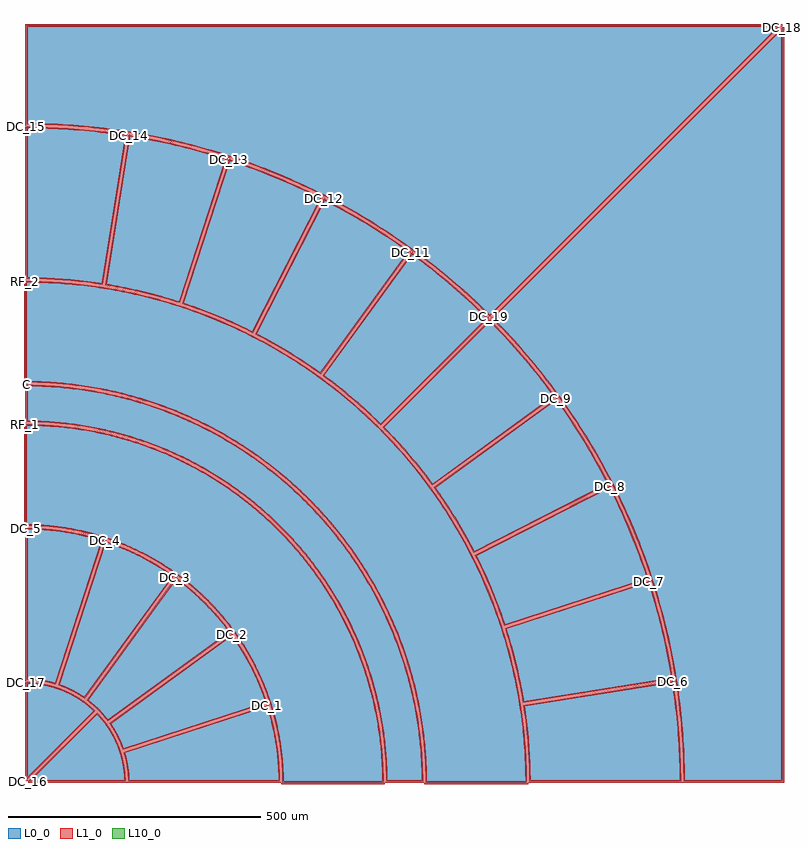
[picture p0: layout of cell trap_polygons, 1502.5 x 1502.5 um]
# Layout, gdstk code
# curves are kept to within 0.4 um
import gdstk
lib = gdstk.Library(unit=1e-6, precision=1e-09)
def P(c, l, *ps):  # polygons
    for p in ps: c.add(gdstk.Polygon(p, *l))
L0_0 = (0, 0)
L1_0 = (1, 0)
L10_0 = (10, 0)

trap_polygons = lib.new_cell('trap_polygons')
P(trap_polygons, L0_0, [(168.53,172.066),(123.841,214.523),(77.191,254.817),(28.686,292.857),(-21.566,328.558),(-73.452,361.839),(-108.893,382.645),(-135.896,397.51),(-190.918,425.3),(-247.195,450.454),(-304.6,472.915),(-363.004,492.633),(-422.275,509.563),(-452.195,516.971),(-492.346,525.742),(-532.753,533.24),(-563.203,538.025),(-624.399,545.425),(-685.878,549.919),(-747.5,551.498),(-747.5,747.5),(743.964,747.5)],
  [(747.5,743.964),(747.5,-747.5),(551.498,-747.5),(549.919,-685.878),(545.425,-624.399),(538.025,-563.203),(533.24,-532.753),(525.742,-492.346),(516.971,-452.195),(509.563,-422.275),(492.633,-363.004),(472.915,-304.6),(450.454,-247.195),(425.3,-190.918),(397.51,-135.896),(382.645,-108.893),(361.839,-73.452),(328.558,-21.566),(292.857,28.686),(254.817,77.191),(214.523,123.841),(172.066,168.53)],
  [(-747.5,-551.516),(-727.732,-552.753),(-709.676,-555.639),(-690.507,-560.625),(-673.334,-566.903),(-656.811,-574.734),(-639.808,-584.894),(-625.083,-595.734),(-611.418,-607.883),(-747.5,-743.964)],
  [(-743.964,-747.5),(-607.883,-611.418),(-595.734,-625.083),(-584.894,-639.808),(-574.734,-656.811),(-566.903,-673.334),(-560.625,-690.507),(-555.639,-709.676),(-552.753,-727.732),(-551.516,-747.5)],
  [(-747.5,546.498),(-695.239,545.343),(-643.067,542.083),(-601.451,537.962),(-549.652,530.927),(-596.583,234.619),(-636.096,239.969),(-675.791,243.733),(-707.636,245.599),(-747.5,246.497)],
  [(-544.714,530.144),(-503.534,522.858),(-452.424,511.888),(-401.798,498.866),(-351.738,483.815),(-444.443,198.497),(-482.633,209.962),(-521.251,219.89),(-560.235,228.265),(-591.644,233.837)],
  [(-346.983,482.27),(-297.636,465.022),(-249.025,445.8),(-201.229,424.633),(-163.63,406.323),(-299.827,139.02),(-335.754,156.318),(-372.343,172.165),(-409.537,186.535),(-439.688,196.952)],
  [(-159.175,404.053),(-113.134,379.298),(-68.129,352.708),(-32.919,330.142),(10.04,300.358),(-166.296,57.652),(-199.074,80.357),(-225.934,97.566),(-260.261,117.853),(-295.372,136.75)],
  [(14.085,297.419),(55.686,265.767),(95.978,232.463),(127.224,204.668),(164.994,168.53),(-47.138,-43.603),(-70.108,-21.468),(-99.798,5.149),(-130.529,30.556),(-162.251,54.713)],
  [(168.53,164.994),(204.668,127.224),(232.463,95.978),(265.767,55.686),(297.419,14.085),(54.713,-162.251),(30.556,-130.529),(5.149,-99.798),(-21.468,-70.108),(-43.603,-47.138)],
  [(300.358,10.04),(330.142,-32.919),(352.708,-68.129),(379.298,-113.134),(404.053,-159.175),(136.75,-295.372),(117.853,-260.261),(97.566,-225.934),(80.357,-199.074),(57.652,-166.296)],
  [(406.323,-163.63),(424.633,-201.229),(445.8,-249.025),(465.022,-297.636),(482.27,-346.983),(196.952,-439.688),(186.535,-409.537),(172.165,-372.343),(156.318,-335.754),(139.02,-299.827)],
  [(483.815,-351.738),(498.866,-401.798),(511.888,-452.424),(522.858,-503.534),(530.144,-544.714),(233.837,-591.644),(228.265,-560.235),(219.89,-521.251),(209.962,-482.633),(198.497,-444.443)],
  [(530.927,-549.652),(537.962,-601.451),(542.083,-643.067),(545.343,-695.239),(546.498,-747.5),(246.497,-747.5),(245.599,-707.636),(243.733,-675.791),(239.969,-636.096),(234.619,-596.583)],
  [(-747.5,-246.506),(-708.271,-248.232),(-673.175,-252.395),(-634.632,-259.896),(-596.789,-270.376),(-689.497,-555.702),(-704.078,-551.749),(-717.42,-549.125),(-732.411,-547.262),(-747.5,-546.515)],
  [(-592.034,-271.921),(-555.259,-285.685),(-523.167,-300.49),(-488.828,-319.534),(-456.076,-341.196),(-632.417,-583.908),(-643.771,-576.427),(-656.94,-569.024),(-670.623,-562.619),(-684.742,-557.247)],
  [(-452.031,-344.134),(-424.294,-366.036),(-395.363,-392.586),(-368.589,-421.309),(-344.134,-452.031),(-586.847,-628.372),(-596.319,-616.604),(-605.571,-606.639),(-616.604,-596.319),(-628.372,-586.847)],
  [(-341.196,-456.076),(-319.534,-488.828),(-300.49,-523.167),(-285.685,-555.259),(-271.921,-592.034),(-557.247,-684.742),(-562.619,-670.623),(-569.024,-656.94),(-576.427,-643.771),(-583.908,-632.417)],
  [(-270.376,-596.789),(-259.896,-634.632),(-252.395,-673.175),(-248.232,-708.271),(-246.506,-747.5),(-546.515,-747.5),(-547.262,-732.411),(-549.125,-717.42),(-551.749,-704.078),(-555.702,-689.497)],
  [(-747.5,36.496),(-710.604,35.513),(-667.673,32.179),(-631.067,27.456),(-594.723,21.02),(-558.721,12.886),(-523.14,3.072),(-488.059,-8.401),(-447.865,-23.848),(-414.13,-38.823),(-381.134,-55.363),(-348.951,-73.434),(-312.524,-96.397),(-282.342,-117.641),(-253.189,-140.278),(-225.13,-164.258),(-193.861,-193.861),(-164.258,-225.13),(-140.278,-253.189),(-117.641,-282.342),(-96.397,-312.524),(-73.434,-348.951),(-55.363,-381.134),(-38.823,-414.13),(-23.848,-447.865),(-8.401,-488.059),(3.072,-523.14),(12.886,-558.721),(21.02,-594.723),(27.456,-631.067),(32.179,-667.673),(35.513,-710.604),(36.496,-747.5),(-36.504,-747.5),(-37.407,-714.042),(-39.877,-680.664),(-44.733,-641.92),(-50.578,-608.965),(-57.962,-576.319),(-68.499,-538.721),(-79.157,-506.994),(-91.291,-475.801),(-104.875,-445.212),(-119.878,-415.293),(-139.132,-381.323),(-157.094,-353.081),(-179.695,-321.24),(-200.43,-294.967),(-222.374,-269.695),(-245.479,-245.479),(-269.695,-222.374),(-294.967,-200.43),(-321.24,-179.695),(-353.081,-157.094),(-381.323,-139.132),(-415.293,-119.878),(-445.212,-104.875),(-475.801,-91.291),(-506.994,-79.157),(-538.721,-68.499),(-576.319,-57.962),(-608.965,-50.578),(-641.92,-44.733),(-680.664,-39.877),(-714.042,-37.407),(-747.5,-36.504)],
  [(-750,241.5),(-703.294,240.399),(-656.692,237.1),(-602.591,230.481),(-556.568,222.449),(-510.974,212.257),(-458.459,197.669),(-414.141,182.883),(-370.569,166.027),(-320.807,143.793),(-279.18,122.583),(-238.598,99.435),(-199.152,74.402),(-154.683,42.887),(-117.994,13.964),(-82.708,-16.656),(-48.904,-48.904),(-16.656,-82.708),(13.964,-117.994),(42.887,-154.683),(74.402,-199.152),(99.435,-238.598),(122.583,-279.18),(143.793,-320.807),(166.027,-370.569),(182.883,-414.141),(197.669,-458.459),(212.257,-510.974),(222.449,-556.568),(230.481,-602.591),(237.1,-656.692),(240.399,-703.294),(241.5,-750),(41.5,-750),(40.89,-718.926),(38.548,-681.704),(35.259,-650.799),(30.759,-620.046),(25.055,-589.494),(16.634,-553.162),(8.315,-523.216),(-3.21,-487.746),(-14.082,-458.629),(-28.624,-424.286),(-41.968,-396.216),(-59.419,-363.256),(-75.135,-336.442),(-91.892,-310.266),(-109.663,-284.768),(-132.289,-255.12),(-160.416,-221.925),(-190.325,-190.325),(-221.925,-160.416),(-255.12,-132.289),(-289.811,-106.029),(-325.893,-81.714),(-363.256,-59.419),(-407.381,-36.498),(-447.106,-18.749),(-487.746,-3.21),(-529.179,10.072),(-571.278,21.058),(-613.918,29.714),(-656.969,36.014),(-706.507,40.304),(-750,41.5)],
  [(-750,-41.5),(-716.625,-42.287),(-683.324,-44.644),(-650.171,-48.568),(-611.779,-55.114),(-579.198,-62.396),(-546.997,-71.205),(-510.004,-83.386),(-478.869,-95.431),(-448.335,-108.93),(-413.564,-126.475),(-384.566,-143.016),(-356.378,-160.904),(-324.602,-183.423),(-298.385,-204.091),(-273.171,-225.971),(-249.015,-249.015),(-225.971,-273.171),(-204.091,-298.385),(-183.423,-324.602),(-160.904,-356.378),(-143.016,-384.566),(-126.475,-413.564),(-108.93,-448.335),(-95.431,-478.869),(-83.386,-510.004),(-71.205,-546.997),(-62.396,-579.198),(-55.114,-611.779),(-48.568,-650.171),(-44.644,-683.324),(-42.287,-716.625),(-41.5,-750),(-241.5,-750),(-242.064,-726.046),(-244.148,-698.171),(-247.151,-674.4),(-251.271,-650.797),(-256.497,-627.413),(-263.979,-600.48),(-271.562,-577.752),(-280.207,-555.405),(-289.895,-533.491),(-300.605,-512.058),(-314.359,-487.723),(-327.198,-467.493),(-340.975,-447.889),(-355.66,-428.957),(-371.221,-410.738),(-390.436,-390.436),(-410.738,-371.221),(-428.957,-355.66),(-447.889,-340.975),(-467.493,-327.198),(-487.723,-314.359),(-512.058,-300.605),(-533.491,-289.895),(-555.405,-280.207),(-577.752,-271.562),(-600.48,-263.979),(-627.413,-256.497),(-650.797,-251.271),(-674.4,-247.151),(-698.171,-244.148),(-726.046,-242.064),(-750,-241.5)])
P(trap_polygons, L1_0, [(-238.718,449.579),(-274.853,464.352),(-303.744,475.264),(-362.26,495.02),(-421.646,511.982),(-481.768,526.114),(-542.492,537.384),(-573.037,541.937),(-613.916,546.88),(-675.475,551.869),(-706.326,553.268),(-745,553.983),(-745,745),(-238.718,745),(-238.718,750),(-750,750),(-750,549.012),(-686.001,547.422),(-624.641,542.937),(-563.561,535.551),(-502.901,525.281),(-462.76,516.844),(-432.84,509.687),(-403.098,501.823),(-363.747,490.246),(-305.455,470.566),(-267.14,455.922),(-238.718,444.149)],
  [(168.53,172.066),(170.298,170.298),(747.5,747.5),(746.464,750),(-238.718,750),(-238.718,745),(737.929,745),(168.52,175.591),(125.519,216.376),(78.78,256.747),(30.181,294.86),(-20.167,330.629),(-72.153,363.974),(-125.659,394.821),(-180.566,423.099),(-238.718,449.579),(-238.718,444.149),(-182.749,418.601),(-155.234,404.84),(-119.069,385.486),(-66.012,354.338),(-14.49,320.713),(27.19,290.854),(67.659,259.373),(114.535,219.526),(144.715,191.746),(166.773,170.287)],
  [(750,-246.229),(745,-246.229),(745,-745),(553.983,-745),(553.268,-706.326),(551.869,-675.475),(546.88,-613.916),(541.937,-573.037),(537.384,-542.492),(526.114,-481.768),(517.009,-441.612),(506.641,-401.762),(495.02,-362.26),(485.488,-332.885),(468.066,-284.455),(452.76,-246.229),(447.33,-246.229),(470.566,-305.455),(490.246,-363.747),(507.144,-422.905),(516.844,-462.76),(523.291,-492.841),(529.024,-523.066),(535.551,-563.561),(542.937,-624.641),(547.422,-686.001),(549.012,-750),(750,-750)],
  [(750,743.964),(747.501,743.964),(745.732,745.732),(168.54,168.54),(212.67,122.162),(252.887,75.602),(290.854,27.19),(326.486,-22.965),(359.703,-74.752),(390.431,-128.053),(418.601,-182.749),(431.706,-210.582),(447.33,-246.229),(452.76,-246.229),(436.255,-208.506),(413.962,-162.115),(394.821,-125.659),(379.714,-98.723),(358.589,-63.38),(342.018,-37.319),(318.972,-3.197),(300.987,21.909),(263.259,70.806),(223.257,117.863),(202.432,140.667),(175.591,168.52),(745,737.929),(745,-246.229),(750,-246.229)],
  [(-607.883,-607.883),(-617.607,-598.761),(-628.367,-589.98),(-639.707,-581.963),(-650.232,-575.508),(-666.931,-566.969),(-679.887,-566.969),(-661.996,-574.868),(-644.98,-584.51),(-629.01,-595.801),(-614.989,-607.918),(-745,-737.929),(-745,-566.969),(-750,-566.969),(-750,-746.464),(-747.5,-747.5)],
  [(-668.118,-566.434),(-691.232,-557.783),(-713.713,-552.303),(-730.521,-549.946),(-745.925,-549.041),(-747.459,-549.016),(-747.5,-551.516),(-750,-551.516),(-750,-566.969),(-745,-566.969),(-745,-554.065),(-728.012,-555.237),(-711.659,-557.787),(-695.579,-561.707),(-679.887,-566.969),(-666.931,-566.969)],
  [(-567.068,-745),(-737.929,-745),(-607.918,-614.989),(-595.801,-629.01),(-584.51,-644.98),(-574.868,-661.996),(-567.068,-679.632),(-567.068,-666.711),(-575.508,-650.232),(-581.963,-639.707),(-589.98,-628.367),(-598.761,-617.607),(-607.883,-607.883),(-745.732,-745.732),(-743.964,-747.501),(-743.964,-750),(-567.068,-750)],
  [(-548.975,-749.959),(-550.102,-728.986),(-553.51,-707.658),(-559.188,-686.82),(-567.068,-666.711),(-567.068,-679.632),(-561.707,-695.579),(-557.787,-711.659),(-555.237,-728.012),(-554.065,-745),(-567.068,-745),(-567.068,-750)],
  [(-747.485,548.998),(-747.515,543.998),(-705.772,543.244),(-653.676,540.41),(-601.737,535.478),(-552.515,528.834),(-598.663,237.464),(-635.81,242.452),(-667.635,245.599),(-707.53,248.097),(-745,248.981),(-745,546.498),(-750,546.498),(-750,244.013),(-707.743,243.101),(-668.047,240.616),(-628.482,236.544),(-594.502,231.775),(-546.792,533.005),(-590.762,539.203),(-642.861,544.574),(-695.133,547.841)],
  [(-544.308,532.611),(-545.12,527.678),(-493.772,518.378),(-452.998,509.454),(-402.469,496.458),(-354.893,482.196),(-446.053,201.632),(-481.962,212.37),(-512.903,220.457),(-551.916,229.165),(-588.787,235.899),(-542.245,529.753),(-547.183,530.536),(-594.502,231.775),(-552.908,224.264),(-514.089,215.599),(-475.649,205.389),(-442.833,195.363),(-348.588,485.42),(-391.047,498.421),(-441.664,511.876),(-492.782,523.279)],
  [(-346.196,484.643),(-347.769,479.897),(-308.303,466.281),(-259.632,447.487),(-211.759,426.747),(-166.999,405.217),(-300.927,142.368),(-334.714,158.592),(-371.396,174.478),(-401.18,186.123),(-436.543,198.542),(-344.605,481.497),(-349.36,483.042),(-442.833,195.363),(-402.926,181.437),(-365.941,166.807),(-329.571,150.708),(-298.727,135.672),(-160.267,407.415),(-200.17,426.898),(-248.059,448.105),(-296.764,467.365)],
  [(-158.027,406.274),(-160.323,401.832),(-123.472,382.21),(-78.341,356.034),(-34.302,328.059),(6.539,299.793),(-166.859,61.131),(-197.692,82.44),(-224.62,99.692),(-259.033,120.03),(-292.017,137.828),(-156.947,402.918),(-161.402,405.188),(-298.728,135.672),(-268.434,119.557),(-234.032,99.596),(-200.456,78.274),(-165.734,54.173),(13.532,300.911),(-22.832,326.396),(-66.814,354.834),(-111.906,381.476)],
  [(15.566,299.433),(12.603,295.405),(45.931,270.26),(86.411,237.346),(125.532,202.827),(161.448,168.519),(-47.15,-40.078),(-74.27,-14.208),(-104.246,12.236),(-128.975,32.514),(-158.769,55.253),(16.107,295.95),(12.062,298.889),(-165.734,54.173),(-138.334,33.518),(-107.478,8.421),(-77.652,-17.891),(-47.127,-47.127),(168.53,168.53),(136.6,199.39),(97.609,234.358),(57.24,267.725)],
  [(170.308,166.752),(166.752,163.237),(195.735,133.188),(230.569,94.346),(263.808,54.133),(293.915,14.629),(55.253,-158.769),(32.514,-128.975),(12.236,-104.246),(-14.208,-74.27),(-40.078,-47.15),(170.298,163.227),(166.762,166.762),(-47.127,-47.127),(-17.891,-77.652),(8.421,-107.478),(33.518,-138.334),(54.173,-165.734),(300.911,13.532),(274.202,49.006),(241.161,89.643),(206.509,128.915)],
  [(302.389,11.497),(298.327,8.582),(322.253,-25.631),(350.581,-69.444),(377.12,-114.362),(400.677,-158.089),(137.828,-292.017),(120.03,-259.033),(99.692,-224.62),(82.44,-197.692),(61.131,-166.859),(301.828,8.017),(298.889,12.062),(54.173,-165.734),(78.274,-200.456),(99.596,-234.032),(119.557,-268.434),(135.672,-298.728),(407.415,-160.267),(386.585,-121.051),(360.307,-75.746),(332.225,-31.536)],
  [(408.557,-162.508),(404.089,-164.752),(426.747,-211.759),(443.494,-249.991),(462.679,-298.508),(479.106,-345.382),(198.542,-436.543),(186.123,-401.18),(174.478,-371.396),(158.592,-334.714),(142.368,-300.927),(407.458,-165.857),(405.188,-161.402),(135.672,-298.727),(150.708,-329.571),(166.807,-365.941),(181.437,-402.926),(195.363,-442.833),(485.42,-348.588),(470.981,-306.596),(452.114,-257.737),(431.294,-209.679)],
  [(486.197,-350.979),(481.433,-352.496),(496.458,-402.469),(507.018,-442.851),(518.378,-493.772),(527.269,-542.638),(235.899,-588.787),(229.165,-551.916),(220.457,-512.903),(212.37,-481.962),(201.632,-446.053),(484.588,-354.115),(483.042,-349.36),(195.363,-442.833),(205.389,-475.649),(215.599,-514.089),(224.264,-552.908),(231.775,-594.502),(533.005,-546.792),(525.312,-503.058),(514.321,-451.85),(501.275,-401.126)],
  [(533.398,-549.276),(528.455,-550.029),(534.241,-591.375),(539.591,-643.273),(542.845,-695.345),(543.983,-745),(248.981,-745),(248.097,-707.53),(245.599,-667.635),(242.452,-635.81),(237.464,-598.663),(531.318,-552.122),(530.536,-547.183),(231.775,-594.502),(236.544,-628.482),(240.616,-668.047),(243.101,-707.743),(244.013,-750),(548.998,-750),(548.241,-705.601),(545.396,-653.304),(540.445,-601.164)],
  [(-747.478,-244.006),(-747.522,-249.006),(-712.374,-250.415),(-673.557,-254.866),(-635.204,-262.329),(-599.947,-272.003),(-691.115,-552.59),(-690.216,-552.866),(-703.514,-549.314),(-717.019,-546.657),(-732.195,-544.771),(-745.94,-544.04),(-745,-544.055),(-745,-246.506),(-750,-246.506),(-750,-548.976),(-734.115,-549.629),(-719.294,-551.359),(-703.19,-554.527),(-687.88,-558.815),(-593.639,-268.771),(-630.22,-258.381),(-668.895,-250.542),(-708.064,-245.741)],
  [(-591.241,-269.551),(-592.828,-274.292),(-559.836,-286.493),(-524.294,-302.722),(-490.124,-321.671),(-459.581,-341.767),(-632.994,-580.448),(-632.224,-580.988),(-643.774,-573.501),(-655.797,-566.801),(-669.647,-560.317),(-682.493,-555.375),(-681.604,-555.68),(-589.657,-272.694),(-594.412,-271.149),(-687.88,-558.814),(-672.974,-564.344),(-659.413,-570.57),(-645.076,-578.559),(-631.841,-587.368),(-452.584,-340.642),(-484.164,-319.457),(-518.524,-300.05),(-554.292,-283.38)],
  [(-450.544,-342.125),(-453.519,-346.144),(-425.911,-367.943),(-397.124,-394.36),(-370.483,-422.941),(-347.644,-451.491),(-586.326,-624.904),(-585.761,-625.655),(-594.431,-614.965),(-603.796,-604.878),(-614.965,-594.431),(-625.655,-585.761),(-624.904,-586.326),(-450.009,-345.604),(-454.054,-342.665),(-631.841,-587.368),(-619.373,-597.233),(-608.4,-607.345),(-597.233,-619.373),(-587.368,-631.841),(-340.642,-452.584),(-364.13,-422.677),(-390.811,-393.602),(-419.677,-366.695)],
  [(-339.16,-454.625),(-343.231,-457.528),(-323.711,-486.791),(-304.496,-520.811),(-287.991,-556.226),(-275.093,-590.436),(-555.68,-681.604),(-555.375,-682.493),(-560.317,-669.647),(-566.801,-655.797),(-573.501,-643.774),(-580.988,-632.224),(-580.448,-632.994),(-339.726,-458.099),(-342.665,-454.054),(-587.368,-631.841),(-578.559,-645.076),(-570.57,-659.413),(-564.344,-672.974),(-558.814,-687.88),(-268.771,-593.639),(-281.867,-557.938),(-298.258,-522.041),(-317.396,-487.531)],
  [(-267.992,-596.038),(-272.761,-597.541),(-263.239,-631.404),(-255.478,-669.697),(-250.724,-708.478),(-249.028,-745),(-544.055,-745),(-544.04,-745.94),(-544.771,-732.195),(-546.657,-717.019),(-549.314,-703.514),(-552.866,-690.216),(-552.59,-691.115),(-269.604,-599.167),(-271.149,-594.412),(-558.815,-687.88),(-554.527,-703.19),(-551.359,-719.294),(-549.629,-734.115),(-548.976,-750),(-244.006,-750),(-245.429,-711.999),(-249.925,-672.794),(-257.462,-634.059)],
  [(-521.999,-71.272),(-548.701,-62.879),(-575.711,-55.537),(-602.987,-49.255),(-630.488,-44.045),(-658.171,-39.913),(-685.995,-36.867),(-713.916,-34.91),(-745,-34.023),(-745,33.978),(-698.484,32.306),(-649.662,27.553),(-619.336,23.035),(-583.212,16.053),(-553.386,8.946),(-521.999,0.109),(-521.999,5.337),(-552.132,13.786),(-582.148,20.939),(-612.421,26.913),(-642.905,31.698),(-679.697,35.862),(-716.643,38.295),(-747.482,38.996),(-747.5,36.496),(-750,36.496),(-750,-38.986),(-725.277,-39.43),(-697.523,-40.939),(-669.85,-43.532),(-647.797,-46.384),(-614.913,-51.951),(-582.325,-59.054),(-550.107,-67.678),(-521.999,-76.554)],
  [(-310.841,-94.517),(-331.861,-80.911),(-358.343,-65.073),(-385.424,-50.282),(-413.062,-36.562),(-441.216,-23.933),(-464.081,-14.628),(-493.053,-4.011),(-521.999,5.337),(-521.999,0.109),(-488.891,-10.758),(-460.186,-21.533),(-426.328,-35.932),(-398.655,-49.134),(-355.513,-72.478),(-334.511,-85.151),(-310.841,-100.549)],
  [(-310.841,-184.495),(-337.845,-164.522),(-361.043,-148.861),(-389.662,-131.281),(-414.12,-117.67),(-439.091,-105.026),(-469.68,-91.155),(-495.645,-80.702),(-521.999,-71.272),(-521.999,-76.554),(-492.233,-87.371),(-461.441,-100.189),(-431.285,-114.436),(-401.83,-130.082),(-377.866,-144.164),(-354.472,-159.171),(-331.682,-175.082),(-310.841,-190.845)],
  [(-146.108,-242.225),(-162.396,-223.462),(-183.433,-200.889),(-205.337,-179.155),(-223.462,-162.396),(-242.102,-146.211),(-266.099,-126.814),(-285.832,-111.981),(-310.841,-94.517),(-310.841,-100.549),(-283.828,-119.651),(-259.538,-138.361),(-235.997,-158.006),(-213.242,-178.557),(-178.557,-213.242),(-146.108,-250.029)],
  [(-146.108,-365.334),(-164.522,-337.845),(-181.079,-315.276),(-198.504,-293.372),(-220.525,-268.012),(-239.768,-247.686),(-263.887,-224.31),(-284.804,-205.712),(-310.841,-184.495),(-310.841,-190.845),(-283.841,-213.142),(-259.177,-235.593),(-235.593,-259.177),(-213.142,-283.841),(-195.332,-305.18),(-178.37,-327.199),(-162.282,-349.864),(-146.108,-374.729)],
  [(-46,-393.776),(-68.157,-352.997),(-90.906,-316.276),(-115.631,-280.855),(-146.108,-242.225),(-146.108,-250.029),(-119.651,-283.828),(-91.732,-324.161),(-66.39,-366.16),(-46,-404.984)],
  [(-46,-619.463),(-54.195,-581.146),(-62.879,-548.701),(-73.076,-516.699),(-84.761,-485.21),(-97.911,-454.304),(-112.496,-424.049),(-128.483,-394.511),(-146.108,-365.334),(-146.108,-374.729),(-127.379,-406.688),(-109.53,-441.262),(-93.599,-476.762),(-79.635,-513.079),(-67.678,-550.107),(-59.054,-582.325),(-51.951,-614.913),(-46,-650.514)],
  [(39.014,-749.982),(37.676,-704.316),(33.278,-655.146),(26.913,-612.421),(16.788,-564.105),(3.662,-516.516),(-10.246,-475.62),(-26.371,-435.546),(-46,-393.776),(-46,-404.984),(-26.156,-448.825),(-10.758,-488.891),(2.424,-529.74),(13.35,-571.249),(21.989,-613.293),(27.553,-649.662),(31.879,-692.367),(33.861,-735.244),(33.978,-745),(-34.023,-745),(-34.91,-713.916),(-37.389,-680.421),(-41.436,-647.078),(-46,-619.463),(-46,-650.514),(-40.939,-697.523),(-39.43,-725.277),(-38.986,-750)],
  [(-481.545,-2.762),(-516.532,8.9),(-546.506,17.48),(-576.794,24.878),(-613.488,32.177),(-650.485,37.739),(-681.489,41.039),(-712.597,43.119),(-747.5,43.99),(-747.5,238.99),(-718.935,238.512),(-687.9,237.048),(-633.756,232.145),(-595.286,226.824),(-557.056,219.997),(-519.123,211.674),(-481.545,201.868),(-481.545,207.058),(-517.955,216.536),(-556.08,224.901),(-586.798,230.511),(-625.419,236.162),(-664.231,240.293),(-710.976,243.234),(-749.99,244),(-750,241.5),(-752.5,241.5),(-752.5,39.01),(-725.217,38.611),(-694.275,37.03),(-663.42,34.235),(-632.697,30.231),(-596.074,23.84),(-553.784,14.212),(-518.002,4.121),(-481.545,-8.079)],
  [(-234.338,99.772),(-264.31,117.261),(-291.791,132.089),(-326.775,149.398),(-355.235,162.248),(-384.084,174.198),(-420.65,187.851),(-450.271,197.733),(-481.545,207.058),(-481.545,201.868),(-444.382,190.595),(-407.69,177.871),(-371.526,163.717),(-335.946,148.154),(-287.217,124.044),(-259.991,109.077),(-234.338,93.923)],
  [(-234.338,-146.238),(-263.352,-122.617),(-293.446,-100.389),(-319.301,-82.966),(-351.201,-63.418),(-383.986,-45.394),(-417.584,-28.934),(-451.92,-14.076),(-481.545,-2.762),(-481.545,-8.079),(-448.063,-21.059),(-414.06,-36.091),(-380.803,-52.709),(-353.713,-67.741),(-322.014,-87.166),(-291.265,-108.063),(-261.535,-130.385),(-234.338,-152.836)],
  [(-45.394,-48.892),(-63.89,-30.772),(-86.82,-9.575),(-110.405,10.89),(-134.621,30.605),(-159.444,49.549),(-184.85,67.705),(-210.813,85.053),(-234.338,99.772),(-234.338,93.923),(-207.016,76.613),(-174.982,54.659),(-149.991,36.2),(-119.588,12.038),(-84.391,-18.505),(-45.394,-55.99)],
  [(-45.394,-383.986),(-63.418,-351.201),(-82.966,-319.301),(-103.995,-288.358),(-126.458,-258.439),(-150.306,-229.612),(-179.808,-197.445),(-206.47,-171.199),(-234.338,-146.238),(-234.338,-152.836),(-209.892,-174.844),(-183.398,-200.925),(-158.162,-228.225),(-134.24,-256.684),(-108.063,-291.265),(-87.166,-322.014),(-64.65,-359.083),(-45.394,-394.976)],
  [(54.659,-166.429),(30.605,-134.621),(5.844,-104.449),(-20.083,-75.272),(-45.394,-48.892),(-45.394,-55.99),(-18.505,-84.391),(7.063,-113.622),(31.463,-143.835),(54.659,-174.982)],
  [(54.659,-747.5),(43.99,-747.5),(43.388,-718.828),(42.017,-693.922),(36.933,-644.302),(28.744,-595.098),(22.062,-564.644),(15.859,-540.485),(3.189,-498.717),(-11.757,-457.709),(-28.934,-417.584),(-45.394,-383.986),(-45.394,-394.976),(-33.475,-419.677),(-23.453,-442.347),(-14.148,-465.32),(-3.539,-494.429),(7.672,-529.876),(18.623,-571.843),(28.293,-620.457),(34.235,-663.42),(37.808,-706.644),(39.01,-752.5),(54.659,-752.5)],
  [(244.01,-752.49),(243.234,-710.976),(240.936,-672.012),(237.11,-633.168),(231.762,-594.504),(224.901,-556.08),(216.536,-517.955),(206.681,-480.188),(195.35,-442.837),(182.562,-405.96),(168.336,-369.613),(152.694,-333.852),(135.661,-298.733),(117.261,-264.31),(97.524,-230.636),(76.481,-197.763),(54.659,-166.429),(54.659,-174.982),(80.853,-213.525),(101.274,-246.558),(120.383,-280.367),(141.539,-321.889),(154.546,-350.104),(169.549,-385.925),(183.134,-422.307),(192.966,-451.779),(201.868,-481.545),(211.674,-519.123),(219.997,-557.056),(226.824,-595.286),(232.145,-633.756),(235.951,-672.404),(238.237,-711.172),(238.99,-747.5),(54.659,-747.5),(54.659,-752.5)],
  [(-569.374,-271.988),(-588.28,-265.265),(-611.294,-258.185),(-634.616,-252.197),(-658.193,-247.315),(-681.975,-243.548),(-701.911,-241.268),(-725.929,-239.567),(-747.5,-239.01),(-747.5,-44.01),(-700.137,-45.763),(-656.016,-50.284),(-612.266,-57.566),(-569.374,-67.498),(-569.374,-62.33),(-594.9,-56.123),(-616.772,-51.594),(-660.888,-44.606),(-705.356,-40.403),(-749.99,-39),(-750,-41.5),(-752.5,-41.5),(-752.5,-243.99),(-714.263,-245.264),(-674.772,-249.623),(-647.39,-254.513),(-620.318,-260.9),(-593.637,-268.765),(-569.374,-277.341)],
  [(-405.033,-128.3),(-442.228,-109.065),(-483.08,-91.005),(-524.985,-75.545),(-569.374,-62.33),(-569.374,-67.498),(-526.567,-80.288),(-484.957,-95.639),(-444.392,-113.573),(-405.033,-134.018)],
  [(-405.033,-373.018),(-424.276,-356.268),(-443.185,-341.361),(-462.775,-327.362),(-483.003,-314.301),(-503.824,-302.207),(-525.191,-291.108),(-547.057,-281.027),(-569.374,-271.988),(-569.374,-277.341),(-545.402,-287.209),(-520.281,-299.151),(-495.854,-312.455),(-472.194,-327.081),(-452.581,-340.637),(-436.738,-352.63),(-421.379,-365.235),(-405.033,-379.825)],
  [(-282.636,-214.197),(-309.824,-191.64),(-341.171,-168.296),(-373.754,-146.709),(-405.033,-128.3),(-405.033,-134.018),(-371.706,-153.905),(-339.522,-175.592),(-308.579,-199.016),(-282.636,-220.847)],
  [(-282.636,-543.38),(-292.888,-521.594),(-306.129,-496.821),(-318.548,-476.192),(-334.246,-452.898),(-351.2,-430.501),(-366.693,-412.07),(-385.842,-391.517),(-405.033,-373.018),(-405.033,-379.825),(-383.874,-400.733),(-365.235,-421.379),(-347.758,-443.019),(-329.276,-468.881),(-316.501,-489.012),(-304.688,-509.723),(-293.864,-530.966),(-282.636,-556.078)],
  [(-174.789,-332.085),(-198.623,-301.108),(-224.122,-271.488),(-251.211,-243.314),(-282.636,-214.197),(-282.636,-220.847),(-250.783,-250.783),(-224.105,-278.969),(-199.016,-308.579),(-174.789,-340.655)],
  [(-174.789,-747.5),(-239.01,-747.5),(-239.772,-721.92),(-242.086,-693.926),(-245.291,-670.062),(-250.446,-642.449),(-256.067,-619.036),(-264.01,-592.092),(-273.421,-565.626),(-282.636,-543.38),(-282.636,-556.078),(-273.914,-578.599),(-265.215,-605.019),(-257.981,-631.877),(-252.233,-659.092),(-248.504,-682.641),(-245.887,-706.339),(-244.39,-730.135),(-243.99,-752.5),(-174.789,-752.5)],
  [(-38.99,-752.49),(-39.548,-722.086),(-41.192,-694.216),(-43.928,-666.431),(-47.754,-638.775),(-52.662,-611.291),(-58.645,-584.02),(-65.694,-557.006),(-73.799,-530.289),(-82.946,-503.911),(-93.122,-477.912),(-104.31,-452.333),(-116.494,-427.213),(-129.655,-402.59),(-143.773,-378.504),(-158.825,-354.99),(-174.789,-332.085),(-174.789,-340.655),(-156.894,-367.036),(-142.316,-390.617),(-128.675,-414.751),(-113.573,-444.392),(-104.287,-464.533),(-93.578,-490.104),(-83.88,-516.075),(-76.861,-537.114),(-69.022,-563.706),(-63.507,-585.188),(-57.566,-612.266),(-52.692,-639.557),(-48.894,-667.019),(-46.176,-694.608),(-44.544,-722.283),(-44.01,-747.5),(-174.789,-747.5),(-174.789,-752.5)])
P(trap_polygons, L10_0, [(0,0),(0,0),(0,0),(0,0)])
trap_polygons.add(gdstk.Label('DC_19', (168.53,172.066), layer=2, texttype=0))
trap_polygons.add(gdstk.Label('DC_18', (747.5,743.964), layer=2, texttype=0))
trap_polygons.add(gdstk.Label('DC_17', (-747.5,-551.516), layer=2, texttype=0))
trap_polygons.add(gdstk.Label('DC_16', (-743.964,-747.5), layer=2, texttype=0))
trap_polygons.add(gdstk.Label('DC_15', (-747.5,546.498), layer=2, texttype=0))
trap_polygons.add(gdstk.Label('DC_14', (-544.714,530.144), layer=2, texttype=0))
trap_polygons.add(gdstk.Label('DC_13', (-346.983,482.27), layer=2, texttype=0))
trap_polygons.add(gdstk.Label('DC_12', (-159.175,404.053), layer=2, texttype=0))
trap_polygons.add(gdstk.Label('DC_11', (14.085,297.419), layer=2, texttype=0))
trap_polygons.add(gdstk.Label('DC_10', (168.53,164.994), layer=2, texttype=0))
trap_polygons.add(gdstk.Label('DC_9', (300.358,10.04), layer=2, texttype=0))
trap_polygons.add(gdstk.Label('DC_8', (406.323,-163.63), layer=2, texttype=0))
trap_polygons.add(gdstk.Label('DC_7', (483.815,-351.738), layer=2, texttype=0))
trap_polygons.add(gdstk.Label('DC_6', (530.927,-549.652), layer=2, texttype=0))
trap_polygons.add(gdstk.Label('DC_5', (-747.5,-246.506), layer=2, texttype=0))
trap_polygons.add(gdstk.Label('DC_4', (-592.034,-271.921), layer=2, texttype=0))
trap_polygons.add(gdstk.Label('DC_3', (-452.031,-344.134), layer=2, texttype=0))
trap_polygons.add(gdstk.Label('DC_2', (-341.196,-456.076), layer=2, texttype=0))
trap_polygons.add(gdstk.Label('DC_1', (-270.376,-596.789), layer=2, texttype=0))
trap_polygons.add(gdstk.Label('C', (-747.5,36.496), layer=2, texttype=0))
trap_polygons.add(gdstk.Label('RF_2', (-750,241.5), layer=2, texttype=0))
trap_polygons.add(gdstk.Label('RF_1', (-750,-41.5), layer=2, texttype=0))

lib.write_gds('trap_polygons.gds')
